VERSION 5.8 ;
BUSBITCHARS "[]" ;
DIVIDERCHAR "/" ;
UNITS
 DATABASE MICRONS 1000 ;
END UNITS
MANUFACTURINGGRID 0.001 ;
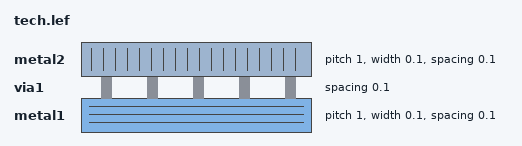
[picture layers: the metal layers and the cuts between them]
LAYER metal1
 TYPE ROUTING ;
 DIRECTION HORIZONTAL ;
 PITCH 1 ;
 WIDTH 0.1 ;
 SPACING 0.1 ;
 ANTENNAAREARATIO 1000 ;
END metal1
LAYER via1
 TYPE CUT ;
 SPACING 0.1 ;
END via1
LAYER metal2
 TYPE ROUTING ;
 DIRECTION VERTICAL ;
 PITCH 1 ;
 WIDTH 0.1 ;
 SPACING 0.1 ;
 ANTENNAAREARATIO 1000 ;
END metal2
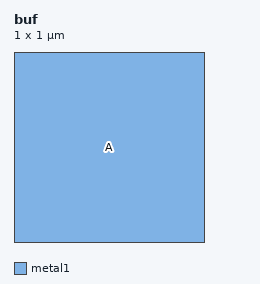
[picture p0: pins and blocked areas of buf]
MACRO buf
 CLASS CORE ;
 ORIGIN 0 0 ;
 SIZE 1 BY 1 ;
 PIN A
  DIRECTION INPUT ;
  USE SIGNAL ;
  ANTENNAGATEAREA 1 ;
  PORT
   LAYER metal1 ;
   RECT 0 0 1 1 ;
  END
 END A
END buf
END LIBRARY
